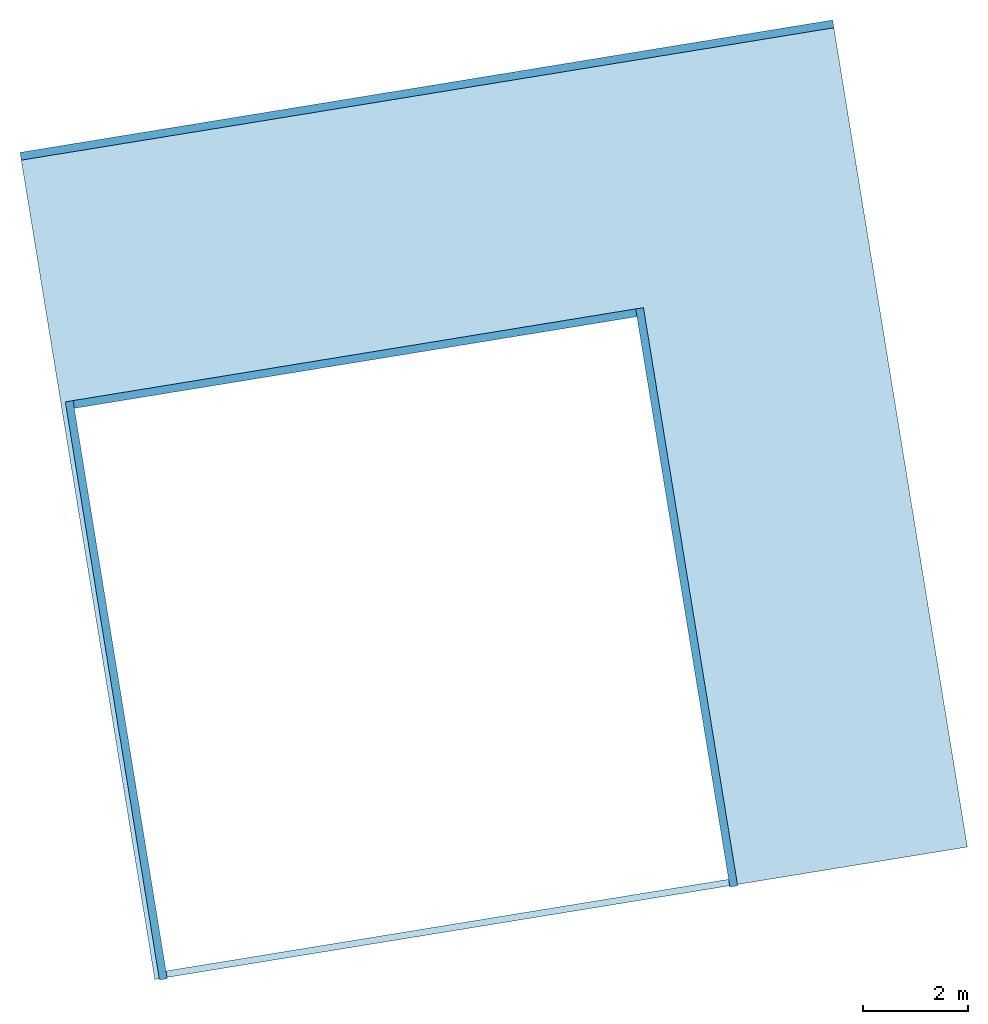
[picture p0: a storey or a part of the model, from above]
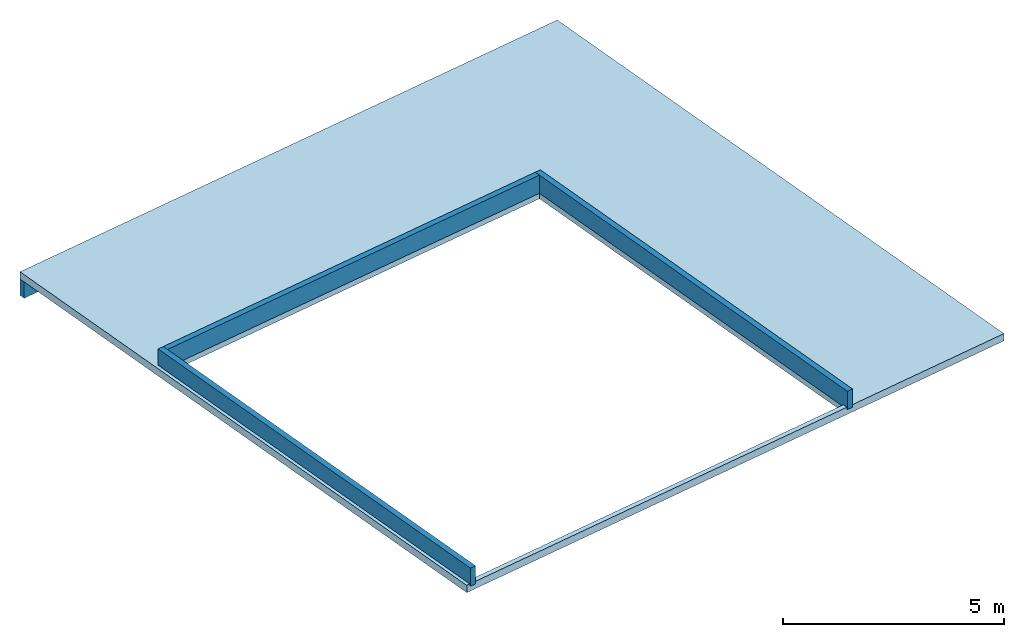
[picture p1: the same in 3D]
Properties of the parts of a building model (IFC2X3)

# File
Description: ViewDefinition [CoordinationView]
File name: BR002-350-101.2 (EDITED).ifc (Edited by Naviate Simple BIM 2022 version 6)
Time: 2026-03-27T07:43:07+01:00
Author: laura
Organization: Avinor
Written by: ODA SDAI 24.12
Made in: Autodesk Revit 25.4.41.14 (ENU) - IFC 25.4.0.27

# IfcProject, 01. Avinor Drift
LongName: Helikopter Terminal; Phase: Som bygget

# IfcSite, Default
RefLatitude: 60, 17, 20, 899658; RefLongitude: 5, 13, 37, 654037; RefElevation: 0 mm
Text - 01_Modellfil: br002-a-200-1-0001; 02_IfcSite: Bergen Lufthavn, Flesland
Other - Project Number: 01. Avinor Drift; Project Address: Bergen lufthavn Flesland; Category: Project Information; Project Status: Som bygget; Client Name: Avinor AS; Project Issue Date: 14.04.16; Project Name: Helikopter Terminal
Identity Data - Author: FDVU; Organization Name: Avinor AS; Workset: Project Info; Organization Description: D&I; Building Name: br002

# IfcBuilding, br002
LongName: br002
Pset_BuildingCommon - NumberOfStoreys: 9
Other - Project Number: 01. Avinor Drift; Project Address: Bergen lufthavn Flesland; Category: Project Information; Project Status: Som bygget; Client Name: Avinor AS; Project Issue Date: 14.04.16; Project Name: Helikopter Terminal
Text - 01_Modellfil: br002-a-200-1-0001; 02_IfcSite: Bergen Lufthavn, Flesland
Identity Data - Author: FDVU; Organization Name: Avinor AS; Workset: Project Info; Organization Description: D&I; Building Name: br002

# IfcBuildingStorey: Level:8mm Head (2)
In: br002
Graphics(Type) - Line Pattern: Centre; Symbol: M_Level Head - Circle; Color: 0; Symbol at End 1 Default: no; Symbol at End 2 Default: yes; Line Weight: 1
Identity Data - Structural: no; Building Story: yes; Workset: Shared Levels and Grids
Pset_AirSideSystemInformation - sets with these values: 2
Constraints(Type) - Elevation Base: Project Base Point
Identity Data(Type) - Workset: Level Types; Type Name: 8mm Head
Other - Family and Type: Level: 8mm Head; Type Id: 305; Category: Levels; Family: Level; Type: 8mm Head
Other(Type) - Category: Levels; Family Name: Level
Name | LongName = Identity Data, Name = Pset_AirSideSystemInformation, Name | Elevation (mm) | Constraints, Elevation (mm) | Computation Height (mm)
H01 | H01 | 3850 | 52210 | 350
Tak | Tak | 7600 | 55960 | 0

# IfcColumn: M_Rectangular Column:100 x 200 mm (2)
In: H01
Type - PredefinedType: COLUMN; Material: Concrete, Cast In Situ
Type - Other - Category: Columns; Family Name: M_Rectangular Column
Type - Dimensions - Depth: 200 mm; Offset Base: 0 mm; Offset Top: 0 mm; Width: 100 mm
Type - Graphics - Coarse Scale Fill Color: 0
Type - Identity Data - OmniClass Number: 23.25.30.11.14.11; OmniClass Title: Columns; Type Name: 100 x 200 mm; Workset: Family : Columns : M_Rectangular Column
Type - Materials and Finishes - Material: Concrete, Cast In Situ
Pset_QuantityTakeOff - Reference: 100 x 200 mm; sets with these values: 2
ePset_SimplebimBasicQuantities - Height (Simplebim): 3200 mm
Phasing - Phase Created: Eksisterende
Identity Data - Workset: ARK
Pset_ColumnCommon - IsExternal: no; Reference: 100 x 200 mm
Other - Family and Type: M_Rectangular Column: 100 x 200 mm; Type Id: 561770; Family: M_Rectangular Column; Type: 100 x 200 mm
ePset_Simplebim - Assembly Level: Leaf
Constraints - Room Bounding: yes; Top Offset: 0 mm; Moves With Grids: yes; Base Offset: 0 mm; Base Level: H01; Level: H01; Top Level: H02
ePset_LocationTool - Splitting: ORIGINAL
Name (M_Rectangular Column:100 x 200 mm:...) | Depth (Simplebim) (mm) | Width (Simplebim) (mm) | Weight, as steel (Simplebim) (kg) | Area, sides, net (Simplebim) (m2) | Volume, net (Simplebim) (m3) = Volume (m3)
580538 | 87.3664 | 11 | 24.1411 | 0.629545 | 0.0030753
581145 | 200 | 62 | 311.488 | 1.6768 | 0.03968

# IfcColumn: M_Rectangular Column:200 x 300 mm (2)
In: H01
Type - PredefinedType: COLUMN; Material: Concrete, Cast In Situ
Type - Other - Category: Columns; Family Name: M_Rectangular Column
Type - Dimensions - Depth: 300 mm; Offset Base: 0 mm; Offset Top: 0 mm; Width: 200 mm
Type - Graphics - Coarse Scale Fill Color: 0
Type - Identity Data - OmniClass Number: 23.25.30.11.14.11; OmniClass Title: Columns; Type Name: 200 x 300 mm; Workset: Family : Columns : M_Rectangular Column
Type - Materials and Finishes - Material: Concrete, Cast In Situ
ePset_SimplebimBasicQuantities - Depth (Simplebim): 300 mm; Height (Simplebim): 3200 mm
Phasing - Phase Created: Eksisterende
Other - Family and Type: M_Rectangular Column: 200 x 300 mm; Family: M_Rectangular Column; Type Id: 524380; Type: 200 x 300 mm
ePset_LocationTool - Splitting: ORIGINAL
Pset_ColumnCommon - IsExternal: no; Reference: 200 x 300 mm
Pset_QuantityTakeOff - Reference: 200 x 300 mm; sets with these values: 2
ePset_Simplebim - Assembly Level: Leaf
Constraints - Room Bounding: yes; Top Offset: 0 mm; Moves With Grids: yes; Base Offset: 0 mm; Base Level: H01; Level: H01; Top Level: H02
Identity Data - Workset: RIB
Name (M_Rectangular Column:200 x 300 mm:...) | Width (Simplebim) (mm) | Area, sides, net (Simplebim) (m2) | Weight, as steel (Simplebim) (kg) | Volume, net (Simplebim) (m3) = Volume (m3)
580537 | 87.3664 | 2.47914 | 658.393 | 0.0838717
581144 | 200 | 3.2 | 1507.2 | 0.192

# IfcColumn: M_Rectangular Column:300 x 300 mm (2)
In: H01
Type - PredefinedType: COLUMN; Material: Concrete, Cast In Situ
Type - Other - Category: Columns; Family Name: M_Rectangular Column
Type - Dimensions - Depth: 300 mm; Offset Base: 0 mm; Offset Top: 0 mm; Width: 300 mm
Type - Graphics - Coarse Scale Fill Color: 0
Type - Identity Data - OmniClass Number: 23.25.30.11.14.11; OmniClass Title: Columns; Type Name: 300 x 300 mm; Workset: Family : Columns : M_Rectangular Column
Type - Materials and Finishes - Material: Concrete, Cast In Situ
ePset_SimplebimBasicQuantities - Area, sides, net (Simplebim): 3.42 m2; Width (Simplebim): 300 mm; Volume, net (Simplebim): 0.2565 m3; Weight, as steel (Simplebim): 2013.53 kg; Depth (Simplebim): 300 mm; Height (Simplebim): 2850 mm
Pset_QuantityTakeOff - Reference: 300 x 300 mm; sets with these values: 2
Constraints - Room Bounding: yes; Top Offset: 0 mm; Moves With Grids: yes; Base Level: H01; Level: H01; Top Level: H02; Base Offset: 350 mm
Phasing - Phase Created: Eksisterende
Dimensions - Volume: 0.2565 m3
ePset_Simplebim - Assembly Level: Leaf
Other - Family and Type: M_Rectangular Column: 300 x 300 mm; Family: M_Rectangular Column; Type Id: 577384; Type: 300 x 300 mm
Identity Data - Workset: RIB
Pset_ColumnCommon - IsExternal: no; Reference: 300 x 300 mm
ePset_LocationTool - Splitting: ORIGINAL
Name (M_Rectangular Column:300 x 300 mm:...)
581367
581633

# IfcColumn: M_Rectangular Column:563 x 300 mm, M_Rectangular Column:563 x 300 mm:563467
In: H01
Type - PredefinedType: COLUMN; Material: <Unnamed>
Type - Other - Category: Columns; Family Name: M_Rectangular Column
Type - Dimensions - Depth: 563 mm; Offset Base: 0 mm; Offset Top: 0 mm; Width: 300 mm
Type - Graphics - Coarse Scale Fill Color: 0
Type - Identity Data - OmniClass Number: 23.25.30.11.14.11; OmniClass Title: Columns; Type Name: 563 x 300 mm; Workset: Family : Columns : M_Rectangular Column
ePset_SimplebimBasicQuantities - Depth (Simplebim): 563 mm; Area, sides, net (Simplebim): 4.9191 m2; Volume, net (Simplebim): 0.481365 m3; Width (Simplebim): 300 mm; Height (Simplebim): 2850 mm; Weight, as steel (Simplebim): 3778.72 kg
ePset_LocationTool - Splitting: ORIGINAL
Dimensions - Volume: 0.481365 m3
Constraints - Room Bounding: yes; Top Offset: 0 mm; Moves With Grids: yes; Base Level: H01; Level: H01; Top Level: H02; Base Offset: 350 mm
Phasing - Phase Created: Eksisterende
Other - Type Id: 564620; Family and Type: M_Rectangular Column: 563 x 300 mm; Family: M_Rectangular Column; Type: 563 x 300 mm
ePset_Simplebim - Assembly Level: Leaf
Identity Data - Workset: RIB
Pset_QuantityTakeOff - Reference: 563 x 300 mm; sets with these values: 2
Pset_ColumnCommon - IsExternal: no; Reference: 563 x 300 mm

# IfcColumn: M_Rectangular Column:600 x 300 mm, M_Rectangular Column:600 x 300 mm:563978
In: H01
Type - PredefinedType: COLUMN; Material: Gypsum Wall Board
Type - Other - Category: Columns; Family Name: M_Rectangular Column
Type - Dimensions - Depth: 600 mm; Offset Base: 0 mm; Offset Top: 0 mm; Width: 300 mm
Type - Graphics - Coarse Scale Fill Color: 0
Type - Identity Data - OmniClass Number: 23.25.30.11.14.11; OmniClass Title: Columns; Type Name: 600 x 300 mm; Workset: Family : Columns : M_Rectangular Column
Constraints - Room Bounding: yes; Top Offset: 0 mm; Moves With Grids: yes; Base Level: H01; Level: H01; Top Level: H02; Base Offset: 350 mm
Phasing - Phase Created: Eksisterende
ePset_LocationTool - Splitting: ORIGINAL
ePset_SimplebimBasicQuantities - Area, sides, net (Simplebim): 6.27 m2; Volume, net (Simplebim): 0.4275 m3; Width (Simplebim): 300 mm; Depth (Simplebim): 600 mm; Height (Simplebim): 2850 mm; Weight, as steel (Simplebim): 3355.88 kg
Other - Family and Type: M_Rectangular Column: 600 x 300 mm; Type Id: 562945; Family: M_Rectangular Column; Type: 600 x 300 mm
ePset_Simplebim - Assembly Level: Leaf
Pset_QuantityTakeOff - Reference: 600 x 300 mm; sets with these values: 2
Identity Data - Workset: RIB
Dimensions - Volume: 0.4275 m3
Pset_ColumnCommon - IsExternal: no; Reference: 600 x 300 mm

# IfcColumn: M_Rectangular Column:600 x 300 mm, M_Rectangular Column:600 x 300 mm:563728
In: H01
Type - PredefinedType: COLUMN; Material: Metal Deck
Type - Other - Category: Columns; Family Name: M_Rectangular Column
Type - Dimensions - Depth: 600 mm; Offset Base: 0 mm; Offset Top: 0 mm; Width: 300 mm
Type - Graphics - Coarse Scale Fill Color: 0
Type - Identity Data - OmniClass Number: 23.25.30.11.14.11; OmniClass Title: Columns; Type Name: 600 x 300 mm; Workset: Family : Columns : M_Rectangular Column
Constraints - Room Bounding: yes; Top Offset: 0 mm; Moves With Grids: yes; Base Level: H01; Level: H01; Top Level: H02; Base Offset: 350 mm
Phasing - Phase Created: Eksisterende
ePset_SimplebimBasicQuantities - Area, sides, net (Simplebim): 5.13 m2; Volume, net (Simplebim): 0.513 m3; Weight, as steel (Simplebim): 4027.05 kg; Width (Simplebim): 300 mm; Depth (Simplebim): 600 mm; Height (Simplebim): 2850 mm
Other - Family and Type: M_Rectangular Column: 600 x 300 mm; Type Id: 562945; Family: M_Rectangular Column; Type: 600 x 300 mm
ePset_Simplebim - Assembly Level: Leaf
Pset_QuantityTakeOff - Reference: 600 x 300 mm; sets with these values: 2
Identity Data - Workset: RIB
ePset_LocationTool - Splitting: ORIGINAL
Dimensions - Volume: 0.513 m3
Pset_ColumnCommon - IsExternal: no; Reference: 600 x 300 mm

# IfcDoor: M_Door-Double-Sliding:1600 x 2100mm (2)
In: H01
Type - ParameterTakesPrecedence: no; Sizeable: no; Material: Wood - Birch - Solid Stained Light Low Gloss, Glass
Type - Other - Category: Doors; Family Name: M_Door-Double-Sliding
Type - Construction - Function: Interior; Wall Closure: By host
Type - Dimensions - Height: 2100 mm; Thickness: 50 mm; Trim Projection Ext: 25 mm; Trim Projection Int: 25 mm; Trim Width: 80 mm; Width: 1600 mm; Rail Width: 50 mm; Stiles: 50 mm
Type - Identity Data - OmniClass Number: 23.30.10.17.11; OmniClass Title: Sliding Doors; Type Mark: 63; Type Name: 1600 x 2100mm; Workset: Family : Doors : M_Door-Double-Sliding; Assembly Code: C1020; Assembly Description: Interior Doors
Type - Analytical Properties - Analytic Construction: Wood frame, double glass door; Define Thermal Properties by: Schematic Type; Heat Transfer Coefficient (U): 3.12872 W/K/m2; Solar Heat Gain Coefficient: 0; Thermal Resistance (R): 0.319619; Visual Light Transmittance: 0
Type - Pset_DoorCommon - ThermalTransmittance: 3.12872 W/K/m2
Type - Materials and Finishes - Glazing: Glass; Panel Material: Wood - Birch - Solid Stained Light Low Gloss; Trim Material: Paint - Sienna
OverallHeight: 2100 mm; OverallWidth: 1600 mm; Classification: C1020 Interior Doors (Uniformat)
Identity Data - Workset: ARK; Dørautomatikk: no; Dørlukker: no
ePset_LocationTool - Splitting: ORIGINAL
Other - Family and Type: M_Door-Double-Sliding: 1600 x 2100mm; Family: M_Door-Double-Sliding; Type: 1600 x 2100mm; Head Height: 2450 mm; Type Id: 621341
Phasing - Phase Created: Eksisterende
Constraints - Level: H01; Sill Height: 350 mm
Pset_QuantityTakeOff - Reference: 1600 x 2100mm
ePset_SimplebimBasicQuantities - Area, opening (Simplebim): 3.36 m2; Area (Simplebim): 3.36 m2; Width, opening (Simplebim): 1600 mm; Width (Simplebim): 1600 mm; Height (Simplebim): 2100 mm; Height, opening (Simplebim): 2100 mm; Length, frame (Simplebim): 5800 mm
Pset_DoorCommon - IsExternal: no; HandicapAccessible: yes; FireExit: no; Reference: 1600 x 2100mm
ePset_Simplebim - Assembly Level: Leaf
Dimensions - Volume: 0.046665 m3; Area: 4.06461 m2
Name (M_Door-Double-Sliding:1600 x 2100mm:...) | Mark | Host Id
656852 | YDH_18 | 446029
823157 | IDH1_146 | 570435

# IfcDoor: M_Single-Flush:0900 x 2100 mm (4)
In: H01
Type - ParameterTakesPrecedence: no; Sizeable: no; Material: Door - Frame, Door - Panel
Type - Other - Category: Doors; Family Name: M_Single-Flush
Type - Construction - Function: Interior; Wall Closure: By host
Type - Dimensions - Height: 2100 mm; Thickness: 51 mm; Trim Projection Ext: 25 mm; Trim Projection Int: 25 mm; Trim Width: 76 mm; Width: 900 mm
Type - Identity Data - OmniClass Number: 23.30.10.00; OmniClass Title: Doors; Type Mark: 53; Type Name: 0900 x 2100 mm; Workset: Family : Doors : M_Single-Flush
Type - Materials and Finishes - Door Material: Door - Panel; Frame Material: Door - Frame
Type - Analytical Properties - Analytic Construction: Metal; Define Thermal Properties by: Schematic Type; Heat Transfer Coefficient (U): 3.7021 W/K/m2; Solar Heat Gain Coefficient: 0; Thermal Resistance (R): 0.270117; Visual Light Transmittance: 0
Type - Pset_DoorCommon - ThermalTransmittance: 3.7021 W/K/m2
OverallHeight: 2100 mm; OverallWidth: 900 mm
Phasing - Phase Created: Eksisterende
Constraints - Level: H01; Sill Height: 350 mm
Other - Family and Type: M_Single-Flush: 0900 x 2100 mm; Type: 0900 x 2100 mm; Family: M_Single-Flush; Type Id: 584286; Head Height: 2450 mm
ePset_LocationTool - Splitting: ORIGINAL
Identity Data - Workset: ARK; Dørautomatikk: no; Dørlukker: no
ePset_Simplebim - Assembly Level: Leaf
Pset_DoorCommon - Reference: 0900 x 2100 mm; IsExternal: no; HandicapAccessible: no; FireExit: no
Dimensions - Area: 3.1077 m2; Volume: 0.116348 m3
Pset_QuantityTakeOff - Reference: 0900 x 2100 mm
ePset_SimplebimBasicQuantities - Area, opening (Simplebim): 1.89 m2; Area (Simplebim): 2.28915 m2; Width, opening (Simplebim): 900 mm; Width (Simplebim): 1052 mm; Height (Simplebim): 2176 mm; Height, opening (Simplebim): 2100 mm; Length, frame (Simplebim): 5404 mm
Name (M_Single-Flush:0900 x 2100 mm:...) | Host Id | Mark
584289 | 570435 | IDH1_145
588197 | 571068 | IDH1_148
588251 | 571068 | IDH1_149
588317 | 571068 | IDH1_150

# IfcRoof: Basic Roof:Sarnafil Tak, Basic Roof:Sarnafil Tak:751543
In: Tak
Material: Asphalt, Bitumen 20 mm, Rigid insulation 50 mm, Structure, Steel Bar Joist Layer 130 mm
Pset_QuantityTakeOff - Reference: Sarnafil Tak
Other - Type Id: 813923; Family: Basic Roof; Family and Type: Basic Roof: Sarnafil Tak; Category: Roofs; Type: Sarnafil Tak
Identity Data - Workset: ARK
Construction - Rafter or Truss: Truss; Rafter Cut: Plumb Cut; Fascia Depth: 0 mm; Maximum Ridge Height: 7800 mm
ePset_SimplebimBasicQuantities - Volume, net (Simplebim): 258.627 m3; Height: 200 mm; Length: 40660 mm; Width: 38150 mm
Constraints - Related to Mass: no; Room Bounding: no; Base Offset From Level: 0 mm; Cutoff Offset: 0 mm; Base Level: Tak
ePset_Simplebim - Assembly Level: Topmost
Dimensions - Area: 1293.14 m2; Volume: 258.627 m3; Slope: 0; Thickness: 200 mm
Phasing - Phase Created: Eksisterende
Pset_RoofCommon - TotalArea: 1293.14 m2; ProjectedArea: 1410.86 m2; IsExternal: yes; Reference: Sarnafil Tak

# IfcSlab: Basic Roof:Sarnafil Tak, Basic Roof:Sarnafil Tak:751543:1
In: Tak
Type - PredefinedType: ROOF
Type - Other - Category: Roofs; Family Name: Basic Roof
Type - Construction - Default Thickness: 200 mm
Type - Graphics - Coarse Scale Fill Color: 0
Type - Identity Data - Type Name: Sarnafil Tak; Workset: Roof Types
Type - Analytical Properties - Absorptance: 0.7; Roughness: 3; Heat Transfer Coefficient (U): 0.150467 W/K/m2; Thermal Mass: 40991; Thermal Resistance (R): 6.64596
Type - Pset_SlabCommon - ThermalTransmittance: 0.150467 W/K/m2
Pset_QuantityTakeOff - Reference: Sarnafil Tak; sets with these values: 2
Pset_SlabCommon - IsExternal: yes; Reference: Sarnafil Tak
ePset_SimplebimBasicQuantities - Area, largest surface, net (Simplebim): 132.254 m2; Area, top, net (Simplebim): 132.254 m2; Volume, net (Simplebim): 26.4508 m3; Area, sides, net (Simplebim): 21.329 m2; Thickness (Simplebim): 200 mm; Perimeter (Simplebim): 106645 mm
ePset_Simplebim - Assembly Level: Leaf
ePset_LocationTool - Splitting: RESULT

# IfcSlab: Floor:Betong 150mm, Floor:Betong 150mm:748018
In: H01
Type - PredefinedType: FLOOR; Material: Concrete, Cast In Situ 150 mm
Type - Other - Category: Floors; Family Name: Floor
Type - Construction - Default Thickness: 150 mm; Function: Interior
Type - Graphics - Coarse Scale Fill Color: 0
Type - Identity Data - Type Name: Betong 150mm; Workset: Floor Types
Type - Materials and Finishes - Structural Material: Concrete, Cast In Situ
Type - Analytical Properties - Absorptance: 0.7; Roughness: 3; Heat Transfer Coefficient (U): 6.97333 W/K/m2; Thermal Mass: 226665; Thermal Resistance (R): 0.143403
Type - Pset_SlabCommon - ThermalTransmittance: 6.97333 W/K/m2
Phasing - Phase Created: Eksisterende
ePset_LocationTool - Splitting: RESULT
Structural - Structural: no
Identity Data - Workset: ARK; Has Association: no
ePset_SimplebimBasicQuantities - Area, largest surface, net (Simplebim): 257.813 m2; Area, top, net (Simplebim): 257.813 m2; Area, sides, net (Simplebim): 9.66435 m2; Perimeter (Simplebim): 64429 mm; Volume, net (Simplebim): 38.672 m3; Thickness (Simplebim): 150 mm
Pset_QuantityTakeOff - Reference: Betong 150mm; sets with these values: 2
Pset_SlabCommon - IsExternal: no; LoadBearing: no; Reference: Betong 150mm
Constraints - Related to Mass: no; Room Bounding: yes; Level: H01
ePset_Simplebim - Assembly Level: Leaf
Other - Type: Betong 150mm; Family and Type: Floor: Betong 150mm; Type Id: 339; Family: Floor

# IfcWall: Basic Wall:A 03 150 mm Planja Sand., Basic Wall:A 03 150 mm Planja Sand.:564973
In: H01
Type - PredefinedType: STANDARD; Material: Metal Deck 5 mm, Polyurethane Foam 140 mm, Metal Deck 5 mm
Type - Other - Category: Walls; Family Name: Basic Wall
Type - Construction - Function: Exterior; Width: 150 mm; Wrapping at Ends: Exterior; Wrapping at Inserts: Both
Type - Graphics - Coarse Scale Fill Color: 12632256; Coarse Scale Fill Pattern: <Solid fill>
Type - Identity Data - Type Mark: A03; Type Name: A 03 150 mm Planja Sand.; Workset: Wall Types
Type - Materials and Finishes - Structural Material: Polyurethane Foam
Type - Analytical Properties - Absorptance: 0.7; Heat Transfer Coefficient (U): 0.22856 W/K/m2; Roughness: 3; Thermal Mass: 45179.5; Thermal Resistance (R): 4.37522
Type - Pset_WallCommon - ThermalTransmittance: 0.22856 W/K/m2
Other - Family: Basic Wall; Type: A 03 150 mm Planja Sand.; Family and Type: Basic Wall: A 03 150 mm Planja Sand.; Type Id: 562544
Pset_QuantityTakeOff - Reference: A 03 150 mm Planja Sand.; sets with these values: 2
Phasing - Phase Created: Eksisterende
Identity Data - Workset: ARK
Structural - Structural Usage: Non-bearing; Structural: no
ePset_LocationTool - Splitting: RESULT
Pset_WallCommon - Reference: A 03 150 mm Planja Sand.; IsExternal: yes; ExtendToStructure: no; LoadBearing: no
ePset_SimplebimBasicQuantities - Volume, net (Simplebim): 0.133594 m3; Area, largest surface, net (Simplebim): 0.890625 m2; Area, side, gross, average (Simplebim): 0.890625 m2; Area, side, net, average (Simplebim): 0.890625 m2; Area, side, net, smaller (Simplebim): 0.890625 m2; Area, side, gross, smaller (Simplebim): 0.890625 m2; Area, side, net, larger (Simplebim): 0.890625 m2; Area, side, gross, larger (Simplebim): 0.890625 m2; Thickness (Simplebim): 150 mm; Length (Simplebim): 313 mm; Height (Simplebim): 2850 mm; Area, side, gross, AABB (Simplebim): 0.89205 m2
Constraints - Location Line: Wall Centerline; Base is Attached: no; Related to Mass: no; Room Bounding: yes; Top is Attached: no; Base Constraint: H01; Top Constraint: Up to level: H02
ePset_Simplebim - Assembly Level: Leaf
Cross-Section Definition - Cross-Section: Vertical

# IfcWall: Basic Wall:E 01 100 mm Innervegg, Basic Wall:E 01 100 mm Innervegg:570435
In: H01
Type - PredefinedType: STANDARD; Material: Gypsum Wall Board 13 mm, Structure, Timber Joist/Rafter Layer 74 mm, Gypsum Wall Board 13 mm
Type - Other - Category: Walls; Family Name: Basic Wall
Type - Construction - Function: Interior; Width: 100 mm; Wrapping at Ends: Exterior; Wrapping at Inserts: Both
Type - Graphics - Coarse Scale Fill Color: 0
Type - Identity Data - Type Mark: E01; Type Name: E 01 100 mm Innervegg; Workset: Wall Types
Type - Materials and Finishes - Structural Material: Structure, Timber Joist/Rafter Layer
Type - Analytical Properties - Absorptance: 0.7; Heat Transfer Coefficient (U): 0.333333 W/K/m2; Roughness: 3; Thermal Mass: 24113.1; Thermal Resistance (R): 3
Type - Pset_WallCommon - ThermalTransmittance: 0.333333 W/K/m2
Other - Family and Type: Basic Wall: E 01 100 mm Innervegg; Family: Basic Wall; Type: E 01 100 mm Innervegg; Type Id: 455070
Pset_WallCommon - Reference: E 01 100 mm Innervegg; IsExternal: no; ExtendToStructure: no; LoadBearing: no
Phasing - Phase Created: Eksisterende
Identity Data - Workset: ARK
Structural - Structural Usage: Non-bearing; Structural: no
ePset_LocationTool - Splitting: RESULT
Constraints - Location Line: Wall Centerline; Base is Attached: no; Related to Mass: no; Room Bounding: yes; Top is Attached: no; Base Constraint: H01; Top Constraint: Up to level: H02
ePset_Simplebim - Assembly Level: Leaf
Cross-Section Definition - Cross-Section: Vertical
ePset_SimplebimBasicQuantities - Area, side, gross, average (Simplebim): 13.9313 m2; Area, side, gross, smaller (Simplebim): 13.9313 m2; Area, side, gross, larger (Simplebim): 13.9313 m2; Area, side, gross, AABB (Simplebim): 12.0412 m2; Area, side, net, larger (Simplebim): 6.79125 m2; Area, side, net, smaller (Simplebim): 6.79125 m2; Area, side, net, average (Simplebim): 6.79125 m2; Area, largest surface, net (Simplebim): 6.79125 m2; Thickness (Simplebim): 100 mm; Height (Simplebim): 2850 mm; Length (Simplebim): 4225 mm; Volume, net (Simplebim): 0.679125 m3
Pset_QuantityTakeOff - Reference: E 01 100 mm Innervegg; sets with these values: 2

# IfcWall: Basic Wall:E 05 Betong 100 mm, Basic Wall:E 05 Betong 100 mm:446029
In: H01
Type - PredefinedType: STANDARD; Material: Concrete, Cast In Situ 100 mm
Type - Other - Category: Walls; Family Name: Basic Wall
Type - Construction - Function: Exterior; Width: 100 mm; Wrapping at Ends: Exterior; Wrapping at Inserts: Both
Type - Graphics - Coarse Scale Fill Color: 12632256; Coarse Scale Fill Pattern: <Solid fill>
Type - Identity Data - Type Mark: E05 100mm; Type Name: E 05 Betong 100 mm; Workset: Wall Types
Type - Materials and Finishes - Structural Material: Concrete, Cast In Situ
Type - Analytical Properties - Absorptance: 0.7; Heat Transfer Coefficient (U): 10.46 W/K/m2; Roughness: 3; Thermal Mass: 151110; Thermal Resistance (R): 0.0956023
Type - Pset_WallCommon - ThermalTransmittance: 10.46 W/K/m2
Pset_ReinforcementBarPitchOfWall - Reference: E 05 Betong 100 mm; sets with these values: 2
ePset_SimplebimBasicQuantities - Area, side, net, smaller (Simplebim): 25.3051 m2; Area, side, net, average (Simplebim): 25.3051 m2; Area, largest surface, net (Simplebim): 25.3051 m2; Area, side, net, larger (Simplebim): 25.3051 m2; Volume, net (Simplebim): 2.53051 m3; Thickness (Simplebim): 100 mm; Height (Simplebim): 3200 mm; Length (Simplebim): 16642 mm; Area, side, gross, average (Simplebim): 58.0651 m2; Area, side, gross, smaller (Simplebim): 58.0651 m2; Area, side, gross, larger (Simplebim): 58.0651 m2; Area, side, gross, AABB (Simplebim): 53.2544 m2
ePset_LocationTool - Splitting: RESULT
Other - Type: E 05 Betong 100 mm; Family: Basic Wall; Family and Type: Basic Wall: E 05 Betong 100 mm; Type Id: 437077
Phasing - Phase Created: Eksisterende
Identity Data - Workset: ARK
Structural - Structural Usage: Non-bearing; Structural: no
Pset_WallCommon - Reference: E 05 Betong 100 mm; IsExternal: yes; ExtendToStructure: yes; LoadBearing: no
Constraints - Location Line: Wall Centerline; Base is Attached: no; Related to Mass: no; Room Bounding: yes; Top is Attached: yes; Base Constraint: H01; Top Constraint: Up to level: H02
ePset_Simplebim - Assembly Level: Leaf
Cross-Section Definition - Cross-Section: Vertical

# IfcWall: Basic Wall:E 05 Betong 150 mm, Basic Wall:E 05 Betong 150 mm:811328
In: Tak
Type - PredefinedType: STANDARD; Material: Concrete, Cast In Situ 150 mm
Type - Other - Category: Walls; Family Name: Basic Wall
Type - Construction - Function: Exterior; Width: 150 mm; Wrapping at Ends: Exterior; Wrapping at Inserts: Both
Type - Graphics - Coarse Scale Fill Color: 12632256; Coarse Scale Fill Pattern: <Solid fill>
Type - Identity Data - Type Mark: E05 150mm; Type Name: E 05 Betong 150 mm; Workset: Wall Types
Type - Materials and Finishes - Structural Material: Concrete, Cast In Situ
Type - Analytical Properties - Absorptance: 0.7; Heat Transfer Coefficient (U): 6.97333 W/K/m2; Roughness: 3; Thermal Mass: 226665; Thermal Resistance (R): 0.143403
Type - Pset_WallCommon - ThermalTransmittance: 6.97333 W/K/m2
ePset_LocationTool - Splitting: RESULT
Phasing - Phase Created: Eksisterende
Identity Data - Workset: ARK
Constraints - Location Line: Wall Centerline; Base is Attached: no; Related to Mass: no; Room Bounding: yes; Top is Attached: no; Base Constraint: Tak; Top Constraint: Up to level: Tak
Structural - Structural Usage: Non-bearing; Structural: no
Pset_ReinforcementBarPitchOfWall - Reference: E 05 Betong 150 mm; sets with these values: 2
Other - Family: Basic Wall; Type Id: 442479; Family and Type: Basic Wall: E 05 Betong 150 mm; Type: E 05 Betong 150 mm
ePset_SimplebimBasicQuantities - Volume, net (Simplebim): 1.05789 m3; Area, side, gross, AABB (Simplebim): 7.05285 m2; Area, side, net, smaller (Simplebim): 7.05262 m2; Area, side, gross, smaller (Simplebim): 7.05262 m2; Area, side, gross, average (Simplebim): 7.05262 m2; Area, side, net, average (Simplebim): 7.05262 m2; Area, side, net, larger (Simplebim): 7.05262 m2; Area, side, gross, larger (Simplebim): 7.05262 m2; Area, largest surface, net (Simplebim): 7.05262 m2; Thickness (Simplebim): 150 mm; Height (Simplebim): 450 mm; Length (Simplebim): 15673 mm
ePset_Simplebim - Assembly Level: Leaf
Cross-Section Definition - Cross-Section: Vertical
Pset_WallCommon - IsExternal: yes; ExtendToStructure: no; LoadBearing: no; Reference: E 05 Betong 150 mm

# IfcWallStandardCase: Basic Wall:A 03 150 mm Planja Sand., Basic Wall:A 03 150 mm Planja Sand.:565062
In: H01
Type - PredefinedType: STANDARD; Material: Metal Deck 5 mm, Polyurethane Foam 140 mm, Metal Deck 5 mm
Type - Other - Category: Walls; Family Name: Basic Wall
Type - Construction - Function: Exterior; Width: 150 mm; Wrapping at Ends: Exterior; Wrapping at Inserts: Both
Type - Graphics - Coarse Scale Fill Color: 12632256; Coarse Scale Fill Pattern: <Solid fill>
Type - Identity Data - Type Mark: A03; Type Name: A 03 150 mm Planja Sand.; Workset: Wall Types
Type - Materials and Finishes - Structural Material: Polyurethane Foam
Type - Analytical Properties - Absorptance: 0.7; Heat Transfer Coefficient (U): 0.22856 W/K/m2; Roughness: 3; Thermal Mass: 45179.5; Thermal Resistance (R): 4.37522
Type - Pset_WallCommon - ThermalTransmittance: 0.22856 W/K/m2
Other - Family: Basic Wall; Type: A 03 150 mm Planja Sand.; Family and Type: Basic Wall: A 03 150 mm Planja Sand.; Type Id: 562544
Pset_QuantityTakeOff - Reference: A 03 150 mm Planja Sand.; sets with these values: 2
Phasing - Phase Created: Eksisterende
Identity Data - Workset: ARK
Structural - Structural Usage: Non-bearing; Structural: no
Dimensions - Length: 3355 mm; Area: 9.348 m2; Volume: 1.4022 m3
Pset_WallCommon - Reference: A 03 150 mm Planja Sand.; IsExternal: yes; ExtendToStructure: no; LoadBearing: no
ePset_SimplebimBasicQuantities - Height (Simplebim): 2850 mm; Thickness (Simplebim): 150 mm; Length (Simplebim): 3280 mm; Area, side, net, larger (Simplebim): 9.348 m2; Area, side, gross, larger (Simplebim): 9.348 m2; Area, side, gross, average (Simplebim): 9.348 m2; Area, side, net, average (Simplebim): 9.348 m2; Area, side, net, smaller (Simplebim): 9.348 m2; Area, side, gross, smaller (Simplebim): 9.348 m2; Area, largest surface, net (Simplebim): 9.348 m2; Area, side, gross, AABB (Simplebim): 9.348 m2; Volume, net (Simplebim): 1.4022 m3
ePset_LocationTool - Splitting: ORIGINAL
ePset_Simplebim - Assembly Level: Leaf
Cross-Section Definition - Cross-Section: Vertical
Constraints - Location Line: Wall Centerline; Base Extension Distance: 0 mm; Base is Attached: no; Related to Mass: no; Room Bounding: yes; Top Extension Distance: 0 mm; Top is Attached: no; Top Offset: 0 mm; Base Constraint: H01; Base Offset: 350 mm; Unconnected Height: 2850 mm; Top Constraint: Up to level: H02

# IfcWallStandardCase: Basic Wall:B 06 126 mm Innervegg- Våtrom, Basic Wall:B 06 126 mm Innervegg- Våtrom:558433
In: H01
Type - PredefinedType: STANDARD; Material: Gypsum Wall Board 13 mm, Rock Wool 100 mm, Gypsum Wall Board 13 mm
Type - Other - Category: Walls; Family Name: Basic Wall
Type - Construction - Function: Interior; Width: 126 mm; Wrapping at Ends: Exterior; Wrapping at Inserts: Both
Type - Graphics - Coarse Scale Fill Color: 0
Type - Identity Data - Type Mark: B06; Type Name: B 06 126 mm Innervegg- Våtrom; Workset: Wall Types
Type - Materials and Finishes - Structural Material: Rock Wool
Type - Analytical Properties - Absorptance: 0.7; Heat Transfer Coefficient (U): 0.335438 W/K/m2; Roughness: 3; Thermal Mass: 38224; Thermal Resistance (R): 2.98118
Type - Pset_WallCommon - ThermalTransmittance: 0.335438 W/K/m2
Pset_QuantityTakeOff - Reference: B 06 126 mm Innervegg- Våtrom; sets with these values: 2
Dimensions - Volume: 2.52564 m3; Length: 6377 mm; Area: 20.0448 m2
Constraints - Location Line: Wall Centerline; Base Extension Distance: 0 mm; Base is Attached: no; Base Offset: 0 mm; Related to Mass: no; Room Bounding: yes; Top Extension Distance: 0 mm; Top is Attached: no; Top Offset: 0 mm; Base Constraint: H01; Unconnected Height: 3200 mm; Top Constraint: Up to level: H02
Phasing - Phase Created: Eksisterende
Identity Data - Workset: ARK
Structural - Structural Usage: Non-bearing; Structural: no
ePset_LocationTool - Splitting: ORIGINAL
Other - Type Id: 481335; Family: Basic Wall; Type: B 06 126 mm Innervegg- Våtrom; Family and Type: Basic Wall: B 06 126 mm Innervegg- Våtrom
ePset_Simplebim - Assembly Level: Leaf
Cross-Section Definition - Cross-Section: Vertical
Pset_WallCommon - Reference: B 06 126 mm Innervegg- Våtrom; IsExternal: no; ExtendToStructure: no; LoadBearing: no
ePset_SimplebimBasicQuantities - Height (Simplebim): 3200 mm; Thickness (Simplebim): 126 mm; Volume, net (Simplebim): 2.52564 m3; Length (Simplebim): 6264 mm; Area, largest surface, net (Simplebim): 20.0448 m2; Area, side, gross, larger (Simplebim): 20.0448 m2; Area, side, net, larger (Simplebim): 20.0448 m2; Area, side, net, average (Simplebim): 20.0448 m2; Area, side, gross, average (Simplebim): 20.0448 m2; Area, side, gross, smaller (Simplebim): 20.0448 m2; Area, side, net, smaller (Simplebim): 20.0448 m2; Area, side, gross, AABB (Simplebim): 20.0448 m2

# IfcWallStandardCase: Basic Wall:B 09 126mm Halvvegg (3)
In: H01
Type - PredefinedType: STANDARD; Material: Gypsum Wall Board 15 mm, Structure, Timber Joist/Rafter Layer 96 mm, Gypsum Wall Board 15 mm
Type - Other - Category: Walls; Family Name: Basic Wall
Type - Construction - Function: Interior; Width: 126 mm; Wrapping at Inserts: Do not wrap
Type - Graphics - Coarse Scale Fill Color: 0
Type - Identity Data - Type Mark: B09; Type Name: B 09 126mm Halvvegg; Workset: Wall Types
Type - Materials and Finishes - Structural Material: Structure, Timber Joist/Rafter Layer
Type - Analytical Properties - Absorptance: 0.7; Heat Transfer Coefficient (U): 0.257324 W/K/m2; Roughness: 3; Thermal Mass: 27835.6; Thermal Resistance (R): 3.88615
Type - Pset_WallCommon - ThermalTransmittance: 0.257324 W/K/m2
Constraints - Base Extension Distance: 0 mm; Base is Attached: no; Base Offset: 0 mm; Related to Mass: no; Room Bounding: yes; Top Extension Distance: 0 mm; Top is Attached: no; Top Offset: 0 mm; Base Constraint: H01; Location Line: Finish Face: Interior; Unconnected Height: 3200 mm; Top Constraint: Up to level: H02
Other - Type: B 09 126mm Halvvegg; Family: Basic Wall; Type Id: 559783; Family and Type: Basic Wall: B 09 126mm Halvvegg
Pset_WallCommon - Reference: B 09 126mm Halvvegg; IsExternal: no; ExtendToStructure: no; LoadBearing: no
Phasing - Phase Created: Eksisterende
Identity Data - Workset: ARK
Pset_ReinforcementBarPitchOfWall - Reference: B 09 126mm Halvvegg; sets with these values: 2
Structural - Structural Usage: Non-bearing; Structural: no
ePset_LocationTool - Splitting: ORIGINAL
ePset_Simplebim - Assembly Level: Leaf
Cross-Section Definition - Cross-Section: Vertical
ePset_SimplebimBasicQuantities - Height (Simplebim): 3200 mm; Thickness (Simplebim): 126 mm
Name (Basic Wall:B 09 126mm Halvvegg:...) | Volume (m3) | Length (mm) | Area (m2) | Volume, net (Simplebim) (m3) | Length (Simplebim) (mm) | Area, side, gross, AABB (Simplebim) (m2) | Area, largest surface, net (Simplebim) (m2) = Area, side, net, larger (Simplebim) (m2) = Area, side, net, smaller (Simplebim) (m2) = Area, side, net, average (Simplebim) (m2) | Area, side, gross, larger (Simplebim) (m2) = Area, side, gross, smaller (Simplebim) (m2) = Area, side, gross, average (Simplebim) (m2)
559884 | 0.42336 | 987 | 3.36 | 0.42336 | 1050 | 3.36 | 3.36 | 3.36
560020 | 2.54416 | 8474.8 | 20.1918 | 2.52035 | 8348.8 | 26.7162 | 20.0028 | 26.9052
560059 | 0.372557 | 987 | 2.9568 | 0.372557 | 924 | 2.9568 | 2.9568 | 2.9568

# IfcWallStandardCase: Basic Wall:E 01 100 mm Innervegg (3)
In: H01
Type - PredefinedType: STANDARD; Material: Gypsum Wall Board 13 mm, Structure, Timber Joist/Rafter Layer 74 mm, Gypsum Wall Board 13 mm
Type - Other - Category: Walls; Family Name: Basic Wall
Type - Construction - Function: Interior; Width: 100 mm; Wrapping at Ends: Exterior; Wrapping at Inserts: Both
Type - Graphics - Coarse Scale Fill Color: 0
Type - Identity Data - Type Mark: E01; Type Name: E 01 100 mm Innervegg; Workset: Wall Types
Type - Materials and Finishes - Structural Material: Structure, Timber Joist/Rafter Layer
Type - Analytical Properties - Absorptance: 0.7; Heat Transfer Coefficient (U): 0.333333 W/K/m2; Roughness: 3; Thermal Mass: 24113.1; Thermal Resistance (R): 3
Type - Pset_WallCommon - ThermalTransmittance: 0.333333 W/K/m2
Other - Family and Type: Basic Wall: E 01 100 mm Innervegg; Family: Basic Wall; Type: E 01 100 mm Innervegg; Type Id: 455070
Pset_WallCommon - Reference: E 01 100 mm Innervegg; IsExternal: no; ExtendToStructure: no; LoadBearing: no
Phasing - Phase Created: Eksisterende
Identity Data - Workset: ARK
Structural - Structural Usage: Non-bearing; Structural: no
ePset_Simplebim - Assembly Level: Leaf
Cross-Section Definition - Cross-Section: Vertical
ePset_LocationTool - Splitting: ORIGINAL
ePset_SimplebimBasicQuantities - Height (Simplebim): 2850 mm; Thickness (Simplebim): 100 mm
Constraints - Location Line: Wall Centerline; Base Extension Distance: 0 mm; Base is Attached: no; Related to Mass: no; Room Bounding: yes; Top Extension Distance: 0 mm; Top is Attached: no; Top Offset: 0 mm; Base Constraint: H01; Base Offset: 350 mm; Unconnected Height: 2850 mm; Top Constraint: Up to level: H02
Pset_QuantityTakeOff - Reference: E 01 100 mm Innervegg; sets with these values: 2
Name (Basic Wall:E 01 100 mm Innervegg:...) | Volume (m3) = Volume, net (Simplebim) (m3) | Area (m2) = Area, largest surface, net (Simplebim) (m2) = Area, side, net, larger (Simplebim) (m2) = Area, side, net, smaller (Simplebim) (m2) = Area, side, net, average (Simplebim) (m2) | Length (mm) | Area, side, gross, larger (Simplebim) (m2) = Area, side, gross, smaller (Simplebim) (m2) = Area, side, gross, average (Simplebim) (m2) = Area, side, gross, AABB (Simplebim) (m2) | Length (Simplebim) (mm)
570493 | 1.1856 | 11.856 | 4260 | 11.856 | 4160
570628 | 1.1856 | 11.856 | 4260 | 11.856 | 4160
571068 | 2.1975 | 21.975 | 9650 | 27.645 | 9700

# IfcWallStandardCase: Basic Wall:E 05 Betong 150 mm (3)
In: Tak
Type - PredefinedType: STANDARD; Material: Concrete, Cast In Situ 150 mm
Type - Other - Category: Walls; Family Name: Basic Wall
Type - Construction - Function: Exterior; Width: 150 mm; Wrapping at Ends: Exterior; Wrapping at Inserts: Both
Type - Graphics - Coarse Scale Fill Color: 12632256; Coarse Scale Fill Pattern: <Solid fill>
Type - Identity Data - Type Mark: E05 150mm; Type Name: E 05 Betong 150 mm; Workset: Wall Types
Type - Materials and Finishes - Structural Material: Concrete, Cast In Situ
Type - Analytical Properties - Absorptance: 0.7; Heat Transfer Coefficient (U): 6.97333 W/K/m2; Roughness: 3; Thermal Mass: 226665; Thermal Resistance (R): 0.143403
Type - Pset_WallCommon - ThermalTransmittance: 6.97333 W/K/m2
Phasing - Phase Created: Eksisterende
Identity Data - Workset: ARK
Structural - Structural Usage: Non-bearing; Structural: no
Pset_ReinforcementBarPitchOfWall - Reference: E 05 Betong 150 mm; sets with these values: 2
Other - Family: Basic Wall; Type Id: 442479; Family and Type: Basic Wall: E 05 Betong 150 mm; Type: E 05 Betong 150 mm
Constraints - Location Line: Wall Centerline; Base Extension Distance: 0 mm; Base is Attached: no; Related to Mass: no; Room Bounding: yes; Top Extension Distance: 0 mm; Top is Attached: no; Top Offset: 0 mm; Base Constraint: Tak; Base Offset: 150 mm; Unconnected Height: 500 mm
ePset_LocationTool - Splitting: ORIGINAL
Dimensions - Length: 11000 mm
ePset_Simplebim - Assembly Level: Leaf
Cross-Section Definition - Cross-Section: Vertical
Pset_WallCommon - IsExternal: yes; ExtendToStructure: no; LoadBearing: no; Reference: E 05 Betong 150 mm
ePset_SimplebimBasicQuantities - Height (Simplebim): 500 mm; Thickness (Simplebim): 150 mm
Name (Basic Wall:E 05 Betong 150 mm:...) | Area (m2) = Area, side, gross, AABB (Simplebim) (m2) = Area, largest surface, net (Simplebim) (m2) = Area, side, net, average (Simplebim) (m2) = Area, side, gross, average (Simplebim) (m2) = Area, side, gross, smaller (Simplebim) (m2) = Area, side, net, smaller (Simplebim) (m2) = Area, side, gross, larger (Simplebim) (m2) = Area, side, net, larger (Simplebim) (m2) | Volume (m3) = Volume, net (Simplebim) (m3) | Length (Simplebim) (mm)
796134 | 5.575 | 0.83625 | 11150
796313 | 5.575 | 0.83625 | 11150
796381 | 5.425 | 0.81375 | 10850

# IfcWindow: M_Fixed:1225 x 2000 mm (10)
In: H01
Type - ParameterTakesPrecedence: no; Sizeable: no; Material: Glass, Aluminium
Type - Other - Category: Windows; Family Name: M_Fixed
Type - Construction - Wall Closure: By host
Type - Dimensions - Default Sill Height: 715 mm; Height: 2000 mm; Width: 1225 mm; Window Inset: 19 mm
Type - Identity Data - OmniClass Number: 23.30.20.17.11; OmniClass Title: Fixed Windows; Type Mark: 23; Type Name: 1225 x 2000 mm; Workset: Family : Windows : M_Fixed
Type - Materials and Finishes - Frame Exterior Material: Aluminium; Frame Interior Material: Aluminium; Glass Pane Material: Glass; Sash: Aluminium
Type - Analytical Properties - Define Thermal Properties by: Schematic Type; Analytic Construction: Triple glazing - 1/4 in thick - clear/clear/clear glass; Heat Transfer Coefficient (U): 1.533 W/K/m2; Solar Heat Gain Coefficient: 0.61; Thermal Resistance (R): 0.652316; Visual Light Transmittance: 0.7
Type - Pset_WindowCommon - ThermalTransmittance: 1.533 W/K/m2
OverallHeight: 2000 mm; OverallWidth: 1225 mm
Dimensions - Area: 3.59282 m2; Volume: 0.0516814 m3
Identity Data - Workset: ARK
Pset_WindowCommon - Reference: 1225 x 2000 mm; IsExternal: yes
ePset_SimplebimBasicQuantities - Height, opening (Simplebim): 2000 mm; Area (Simplebim): 2.45 m2; Area, opening (Simplebim): 2.45 m2; Width, opening (Simplebim): 1225 mm; Width (Simplebim): 1225 mm; Height (Simplebim): 2000 mm; Length, frame (Simplebim): 5225 mm; Perimeter (Simplebim): 6450 mm
Phasing - Phase Created: Eksisterende
Other - Type: 1225 x 2000 mm; Family: M_Fixed; Host Id: 446029; Family and Type: M_Fixed: 1225 x 2000 mm; Type Id: 653633; Head Height: 2715 mm
Constraints - Level: H01; Sill Height: 715 mm
Pset_QuantityTakeOff - Reference: 1225 x 2000 mm
ePset_Simplebim - Assembly Level: Leaf
ePset_LocationTool - Splitting: ORIGINAL
Name (M_Fixed:1225 x 2000 mm:...) | Mark
655532 | 85
655608 | 86
655682 | 87
655764 | 88
655806 | 89
655848 | 90
655908 | 91
655958 | 92
656012 | 93
656064 | 94
